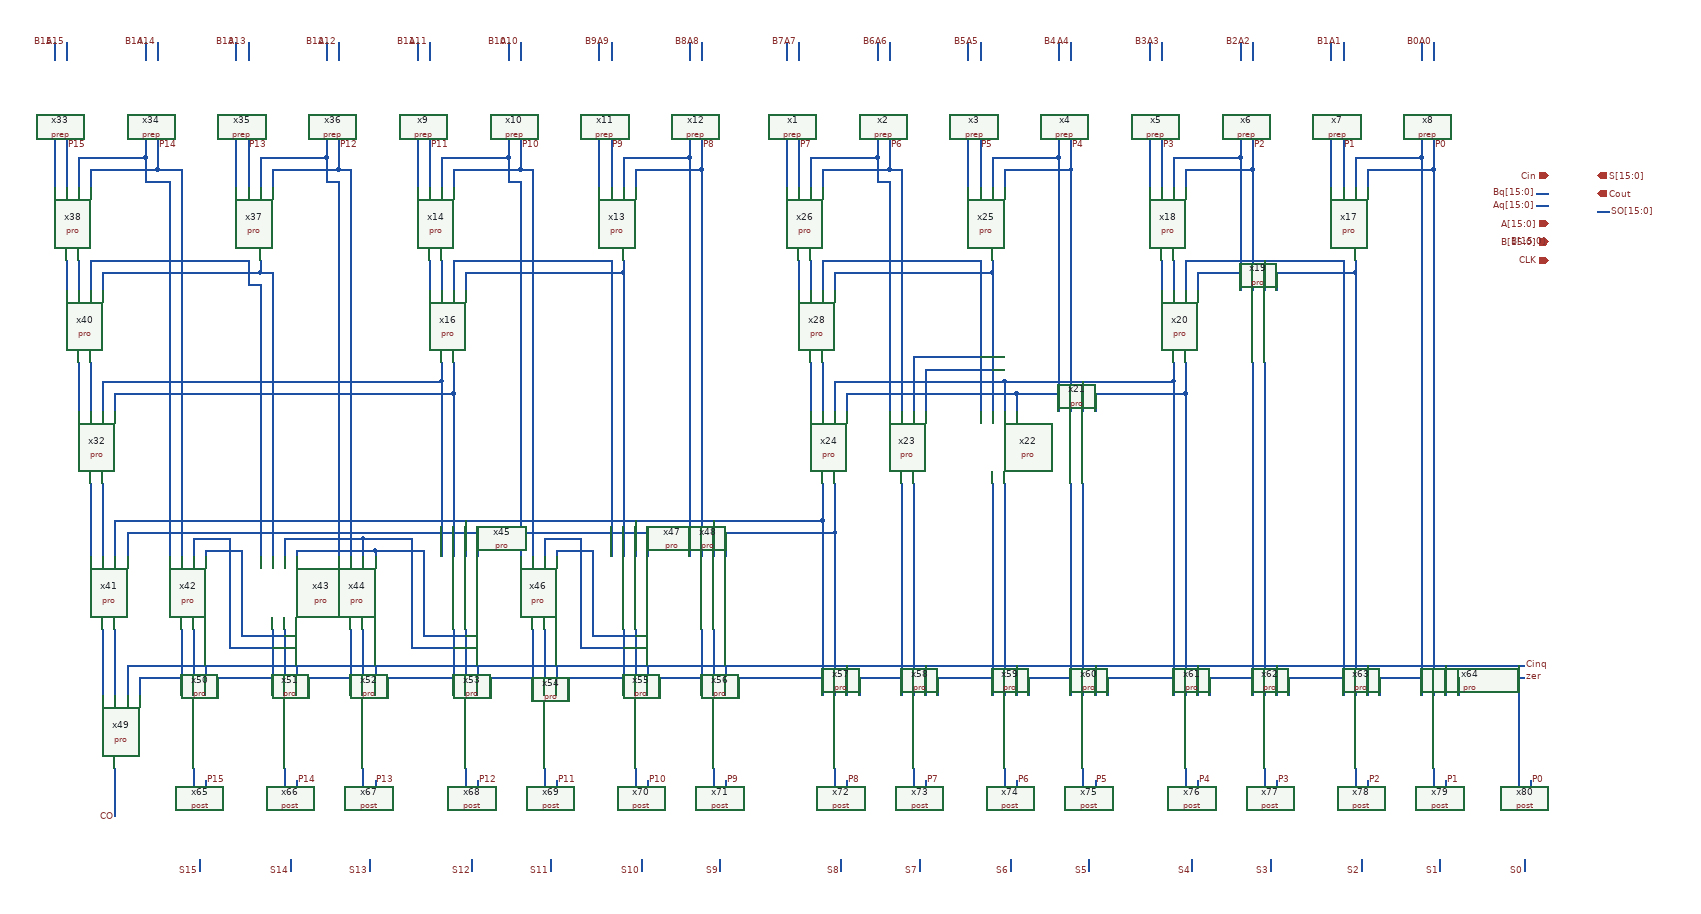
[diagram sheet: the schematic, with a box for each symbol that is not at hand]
v {xschem version=3.4.6 file_version=1.2}
G {}
K {}
V {}
S {}
E {}
N 950 -340 950 -290 {lab=P0}
N 840 -290 840 -260 {lab=P0}
N 930 -340 930 -310 {lab=#net1}
N 820 -310 820 -260 {lab=#net1}
N 800 -340 800 -260 {lab=P1}
N 780 -340 780 -260 {lab=#net2}
N 820 -310 930 -310 {lab=#net1}
N 840 -290 950 -290 {lab=P0}
N 480 -340 480 -260 {lab=#net3}
N 500 -340 500 -260 {lab=P3}
N 520 -310 520 -260 {lab=#net4}
N 520 -310 630 -310 {lab=#net4}
N 630 -340 630 -310 {lab=#net4}
N 650 -340 650 -290 {lab=P2}
N 540 -290 650 -290 {lab=P2}
N 540 -290 540 -260 {lab=P2}
N 500 -140 500 -90 {lab=#net5}
N 520 -140 520 -90 {lab=#net6}
N 540 -140 540 -90 {lab=#net7}
N 540 -140 800 -140 {lab=#net7}
N 560 -120 560 -90 {lab=#net8}
N 560 -120 820 -120 {lab=#net8}
N 820 -140 820 -120 {lab=#net8}
N 630 -310 630 -100 {lab=#net4}
N 650 -290 650 -100 {lab=P2}
N 670 -140 670 -100 {lab=#net7}
N 350 -340 350 -290 {lab=P4}
N 240 -290 240 -260 {lab=P4}
N 330 -340 330 -310 {lab=#net9}
N 220 -310 220 -260 {lab=#net9}
N 200 -340 200 -260 {lab=P5}
N 180 -340 180 -260 {lab=#net10}
N 220 -310 330 -310 {lab=#net9}
N 240 -290 350 -290 {lab=P4}
N -120 -340 -120 -260 {lab=#net11}
N -100 -340 -100 -260 {lab=P7}
N -80 -310 -80 -260 {lab=#net12}
N -80 -310 30 -310 {lab=#net12}
N 30 -340 30 -310 {lab=#net12}
N 50 -340 50 -290 {lab=P6}
N -60 -290 50 -290 {lab=P6}
N -60 -290 -60 -260 {lab=P6}
N -100 -140 -100 -90 {lab=#net13}
N -80 -140 -80 -90 {lab=#net14}
N -60 -140 -60 -90 {lab=#net15}
N -60 -140 200 -140 {lab=#net15}
N -40 -120 -40 -90 {lab=#net16}
N -40 -120 220 -120 {lab=#net16}
N 220 -140 220 -120 {lab=#net16}
N 630 -100 630 -90 {lab=#net4}
N 650 -100 650 -90 {lab=P2}
N 670 -100 670 -90 {lab=#net7}
N 520 30 520 60 {lab=#net17}
N -40 60 -40 110 {lab=#net17}
N 540 30 540 80 {lab=#net18}
N -20 80 -20 110 {lab=#net18}
N -80 30 -80 110 {lab=#net19}
N -60 30 -60 110 {lab=#net20}
N 50 30 50 110 {lab=#net12}
N 70 30 70 110 {lab=P6}
N 200 -140 200 110 {lab=#net15}
N 220 -120 220 110 {lab=#net16}
N 240 60 240 110 {lab=#net17}
N 260 80 260 110 {lab=#net18}
N 330 -310 330 110 {lab=#net9}
N 350 -290 350 110 {lab=P4}
N 370 60 370 110 {lab=#net17}
N 390 80 390 110 {lab=#net18}
N -260 -340 -260 -290 {lab=P8}
N -370 -290 -370 -260 {lab=P8}
N -280 -340 -280 -310 {lab=#net21}
N -390 -310 -390 -260 {lab=#net21}
N -410 -340 -410 -260 {lab=P9}
N -430 -340 -430 -260 {lab=#net22}
N -390 -310 -280 -310 {lab=#net21}
N -370 -290 -260 -290 {lab=P8}
N -730 -340 -730 -260 {lab=#net23}
N -710 -340 -710 -260 {lab=P11}
N -690 -310 -690 -260 {lab=#net24}
N -690 -310 -580 -310 {lab=#net24}
N -580 -340 -580 -310 {lab=#net24}
N -560 -340 -560 -290 {lab=P10}
N -670 -290 -560 -290 {lab=P10}
N -670 -290 -670 -260 {lab=P10}
N -710 -140 -710 -90 {lab=#net25}
N -690 -140 -690 -90 {lab=#net26}
N -670 -140 -670 -90 {lab=#net27}
N -670 -140 -410 -140 {lab=#net27}
N -650 -120 -650 -90 {lab=#net28}
N -650 -120 -390 -120 {lab=#net28}
N -390 -140 -390 -120 {lab=#net28}
N -860 -340 -860 -290 {lab=P12}
N -970 -290 -970 -260 {lab=P12}
N -880 -340 -880 -310 {lab=#net29}
N -990 -310 -990 -260 {lab=#net29}
N -1010 -340 -1010 -260 {lab=P13}
N -1030 -340 -1030 -260 {lab=#net30}
N -990 -310 -880 -310 {lab=#net29}
N -970 -290 -860 -290 {lab=P12}
N -1330 -340 -1330 -260 {lab=#net31}
N -1310 -340 -1310 -260 {lab=P15}
N -1290 -310 -1290 -260 {lab=#net32}
N -1290 -310 -1180 -310 {lab=#net32}
N -1180 -340 -1180 -310 {lab=#net32}
N -1160 -340 -1160 -290 {lab=P14}
N -1270 -290 -1160 -290 {lab=P14}
N -1270 -290 -1270 -260 {lab=P14}
N -1310 -140 -1310 -90 {lab=#net33}
N -1290 -140 -1290 -90 {lab=#net34}
N -1270 -140 -1270 -90 {lab=#net35}
N -1270 -140 -1010 -140 {lab=#net35}
N -1250 -120 -1250 -90 {lab=#net36}
N -1250 -120 -990 -120 {lab=#net36}
N -990 -140 -990 -120 {lab=#net36}
N -690 30 -690 60 {lab=#net37}
N -1250 60 -690 60 {lab=#net37}
N -1250 60 -1250 110 {lab=#net37}
N -670 30 -670 80 {lab=#net38}
N -1230 80 -670 80 {lab=#net38}
N -1230 80 -1230 110 {lab=#net38}
N -1290 30 -1290 110 {lab=#net39}
N -1270 30 -1270 110 {lab=#net40}
N -1270 230 -1270 350 {lab=#net41}
N -1250 230 -1250 350 {lab=#net42}
N -1140 230 -1140 350 {lab=#net32}
N -1120 230 -1120 350 {lab=P14}
N -990 230 -990 350 {lab=#net35}
N -970 230 -970 350 {lab=#net36}
N -860 230 -860 350 {lab=#net29}
N -840 230 -840 350 {lab=P12}
N -690 60 -690 350 {lab=#net37}
N -670 80 -670 350 {lab=#net38}
N -560 30 -560 350 {lab=#net24}
N -540 30 -540 350 {lab=P10}
N -410 -140 -410 350 {lab=#net27}
N -390 -120 -390 350 {lab=#net28}
N -280 -310 -280 350 {lab=#net21}
N -260 -290 -260 350 {lab=P8}
N -60 230 -60 290 {lab=#net43}
N -1230 290 -60 290 {lab=#net43}
N -1230 290 -1230 350 {lab=#net43}
N -1210 310 -1210 350 {lab=#net44}
N -1210 310 -40 310 {lab=#net44}
N -40 230 -40 310 {lab=#net44}
N -220 310 -220 350 {lab=#net44}
N -240 290 -240 350 {lab=#net43}
N -350 310 -350 350 {lab=#net44}
N -370 290 -370 350 {lab=#net43}
N -630 310 -630 350 {lab=#net44}
N -650 290 -650 350 {lab=#net43}
N -1250 470 -1250 580 {lab=#net45}
N -1230 470 -1230 580 {lab=#net46}
N -1120 470 -1120 580 {lab=#net47}
N -1100 470 -1100 580 {lab=#net48}
N -970 470 -970 580 {lab=#net49}
N -950 470 -950 580 {lab=#net50}
N -840 470 -840 580 {lab=#net51}
N -820 470 -820 580 {lab=#net52}
N -670 470 -670 580 {lab=#net53}
N -650 470 -650 580 {lab=#net54}
N -540 470 -540 590 {lab=#net55}
N -520 470 -520 580 {lab=#net56}
N -390 470 -390 580 {lab=#net57}
N -370 470 -370 580 {lab=#net58}
N -260 470 -260 580 {lab=#net59}
N -240 470 -240 580 {lab=#net60}
N -60 290 -60 580 {lab=#net43}
N -40 310 -40 580 {lab=#net44}
N 70 230 70 580 {lab=#net61}
N 90 230 90 580 {lab=#net62}
N 220 230 220 580 {lab=#net63}
N 240 230 240 580 {lab=#net64}
N 350 230 350 580 {lab=#net65}
N 370 230 370 580 {lab=#net66}
N 520 60 520 580 {lab=#net17}
N 540 80 540 580 {lab=#net18}
N 650 30 650 580 {lab=#net67}
N 670 30 670 580 {lab=#net68}
N 800 -140 800 580 {lab=#net7}
N 820 -120 820 580 {lab=#net8}
N 930 -310 930 580 {lab=#net1}
N 950 -290 950 580 {lab=P0}
N -1210 530 -1210 580 {lab=Cinq}
N -1210 530 1100 530 {lab=Cinq}
N -1190 550 -1190 580 {lab=zer}
N -1190 550 1100 550 {lab=zer}
N 990 550 990 580 {lab=zer}
N 970 530 970 580 {lab=Cinq}
N 860 550 860 580 {lab=zer}
N 840 530 840 580 {lab=Cinq}
N 710 550 710 580 {lab=zer}
N 690 530 690 580 {lab=Cinq}
N 560 530 560 580 {lab=Cinq}
N 580 550 580 580 {lab=zer}
N 410 550 410 580 {lab=zer}
N 390 530 390 580 {lab=Cinq}
N 280 550 280 580 {lab=zer}
N 260 530 260 580 {lab=Cinq}
N 130 550 130 580 {lab=zer}
N 110 530 110 580 {lab=Cinq}
N 0 550 0 580 {lab=zer}
N -20 530 -20 580 {lab=Cinq}
N -200 550 -200 580 {lab=zer}
N -220 530 -220 580 {lab=Cinq}
N -330 550 -330 580 {lab=zer}
N -350 530 -350 580 {lab=Cinq}
N -480 550 -480 580 {lab=zer}
N -500 530 -500 580 {lab=Cinq}
N -610 550 -610 580 {lab=zer}
N -630 530 -630 580 {lab=Cinq}
N -780 550 -780 580 {lab=zer}
N -800 530 -800 580 {lab=Cinq}
N -910 550 -910 580 {lab=zer}
N -930 530 -930 580 {lab=Cinq}
N -1060 550 -1060 580 {lab=zer}
N -1080 530 -1080 580 {lab=Cinq}
N -1230 700 -1230 780 {lab=CO}
N -1100 700 -1100 730 {lab=#net69}
N -950 700 -950 730 {lab=#net70}
N -820 700 -820 730 {lab=#net71}
N -650 700 -650 730 {lab=#net72}
N -520 700 -520 730 {lab=#net73}
N -370 700 -370 730 {lab=#net74}
N -240 700 -240 730 {lab=#net75}
N -40 700 -40 730 {lab=#net76}
N 90 700 90 730 {lab=#net77}
N 240 700 240 730 {lab=#net78}
N 370 700 370 730 {lab=#net79}
N 540 700 540 730 {lab=#net80}
N 670 700 670 730 {lab=#net81}
N 820 700 820 730 {lab=#net82}
N 950 700 950 730 {lab=#net83}
N -1330 -500 -1330 -470 {lab=B15}
N -1310 -500 -1310 -470 {lab=A15}
N -1180 -500 -1180 -470 {lab=B14}
N -1160 -500 -1160 -470 {lab=A14}
N -1030 -500 -1030 -470 {lab=B13}
N -1010 -500 -1010 -470 {lab=A13}
N -880 -500 -880 -470 {lab=B12}
N -860 -500 -860 -470 {lab=A12}
N -730 -500 -730 -470 {lab=B11}
N -710 -500 -710 -470 {lab=A11}
N -580 -500 -580 -470 {lab=B10}
N -560 -500 -560 -470 {lab=A10}
N -430 -500 -430 -470 {lab=B9}
N -410 -500 -410 -470 {lab=A9}
N -280 -500 -280 -470 {lab=B8}
N -260 -500 -260 -470 {lab=A8}
N -120 -500 -120 -470 {lab=B7}
N -100 -500 -100 -470 {lab=A7}
N 30 -500 30 -470 {lab=B6}
N 50 -500 50 -470 {lab=A6}
N 180 -500 180 -470 {lab=B5}
N 200 -500 200 -470 {lab=A5}
N 330 -500 330 -470 {lab=B4}
N 350 -500 350 -470 {lab=A4}
N 480 -500 480 -470 {lab=B3}
N 500 -500 500 -470 {lab=A3}
N 630 -500 630 -470 {lab=B2}
N 650 -500 650 -470 {lab=A2}
N 780 -500 780 -470 {lab=B1}
N 800 -500 800 -470 {lab=A1}
N 930 -500 930 -470 {lab=B0}
N 950 -500 950 -470 {lab=A0}
N 1090 530 1090 730 {lab=Cinq}
N 1110 720 1110 730 {lab=P0}
N 970 720 970 730 {lab=P1}
N 840 720 840 730 {lab=P2}
N 690 720 690 730 {lab=P3}
N 560 720 560 730 {lab=P4}
N 390 720 390 730 {lab=P5}
N 260 720 260 730 {lab=P6}
N 110 720 110 730 {lab=P7}
N -20 720 -20 730 {lab=P8}
N -220 720 -220 730 {lab=P9}
N -350 720 -350 730 {lab=P10}
N -500 720 -500 730 {lab=P11}
N -630 720 -630 730 {lab=P12}
N -800 720 -800 730 {lab=P13}
N -930 720 -930 730 {lab=P14}
N -1080 720 -1080 730 {lab=P15}
N 1100 850 1100 870 {lab=S0}
N 960 850 960 870 {lab=S1}
N 830 850 830 870 {lab=S2}
N 680 850 680 870 {lab=S3}
N 550 850 550 870 {lab=S4}
N 380 850 380 870 {lab=S5}
N 250 850 250 870 {lab=S6}
N 100 850 100 870 {lab=S7}
N -30 850 -30 870 {lab=S8}
N -230 850 -230 870 {lab=S9}
N -360 850 -360 870 {lab=S10}
N -510 850 -510 870 {lab=S11}
N -640 850 -640 870 {lab=S12}
N -810 850 -810 870 {lab=S13}
N -940 850 -940 870 {lab=S14}
N -1090 850 -1090 870 {lab=S15}
N 690 -120 690 -90 {lab=#net8}
N 50 -20 50 30 {lab=#net12}
N 70 -40 70 30 {lab=P6}
N 240 60 520 60 {lab=#net17}
N 260 80 540 80 {lab=#net18}
N 90 20 90 110 {lab=#net15}
N 90 20 200 20 {lab=#net15}
N 110 40 110 110 {lab=#net16}
N 110 40 210 40 {lab=#net16}
N 210 40 220 40 {lab=#net16}
N -40 60 240 60 {lab=#net17}
N -20 80 260 80 {lab=#net18}
N 70 -290 70 -40 {lab=P6}
N 50 -290 70 -290 {lab=P6}
N 30 -310 30 -270 {lab=#net12}
N 30 -270 50 -270 {lab=#net12}
N 50 -270 50 -20 {lab=#net12}
N -440 480 -370 480 {lab=#net58}
N -440 340 -440 480 {lab=#net58}
N -500 340 -440 340 {lab=#net58}
N -500 340 -500 350 {lab=#net58}
N -460 500 -390 500 {lab=#net57}
N -460 320 -460 500 {lab=#net57}
N -520 320 -460 320 {lab=#net57}
N -520 320 -520 350 {lab=#net57}
N -580 -310 -580 -270 {lab=#net24}
N -580 -270 -560 -270 {lab=#net24}
N -560 -270 -560 30 {lab=#net24}
N -540 -290 -540 30 {lab=P10}
N -560 -290 -540 -290 {lab=P10}
N -720 480 -650 480 {lab=#net54}
N -720 340 -720 480 {lab=#net54}
N -800 340 -720 340 {lab=#net54}
N -800 340 -800 350 {lab=#net54}
N -740 500 -670 500 {lab=#net53}
N -740 320 -740 500 {lab=#net53}
N -820 320 -740 320 {lab=#net53}
N -820 320 -820 350 {lab=#net53}
N -860 -270 -860 230 {lab=#net29}
N -880 -270 -860 -270 {lab=#net29}
N -880 -310 -880 -270 {lab=#net29}
N -860 -290 -840 -290 {lab=P12}
N -840 -290 -840 230 {lab=P12}
N -950 320 -820 320 {lab=#net53}
N -950 320 -950 350 {lab=#net53}
N -930 340 -930 350 {lab=#net54}
N -930 340 -800 340 {lab=#net54}
N -990 -120 -970 -120 {lab=#net36}
N -970 -120 -970 230 {lab=#net36}
N -1010 -140 -1010 -100 {lab=#net35}
N -1010 -100 -990 -100 {lab=#net35}
N -990 -100 -990 230 {lab=#net35}
N -1020 480 -950 480 {lab=#net50}
N -1020 340 -1020 480 {lab=#net50}
N -1080 340 -1020 340 {lab=#net50}
N -1080 340 -1080 350 {lab=#net50}
N -1040 500 -970 500 {lab=#net49}
N -1040 330 -1040 500 {lab=#net49}
N -1100 330 -1100 350 {lab=#net49}
N -1100 320 -1040 320 {lab=#net49}
N -1040 320 -1040 330 {lab=#net49}
N -1100 320 -1100 330 {lab=#net49}
N -1180 -310 -1180 -270 {lab=#net32}
N -1180 -270 -1160 -270 {lab=#net32}
N -1160 -270 -1150 -270 {lab=#net32}
N -1150 -270 -1140 -270 {lab=#net32}
N -1140 -270 -1140 230 {lab=#net32}
N -1120 -290 -1120 230 {lab=P14}
N -1160 -290 -1120 -290 {lab=P14}
N 1120 -230 1140 -230 {lab=Aq[15:0]}
N 1120 -250 1140 -250 {lab=Bq[15:0]}
N 1220 -220 1240 -220 {lab=SO[15:0]}
C {/home/EE23B038/ee5311/tutorial_9/prep.sym} 480 -390 0 0 {name=x5}
C {/home/EE23B038/ee5311/tutorial_9/prep.sym} 630 -390 0 0 {name=x6}
C {/home/EE23B038/ee5311/tutorial_9/prep.sym} 780 -390 0 0 {name=x7}
C {/home/EE23B038/ee5311/tutorial_9/prep.sym} 930 -390 0 0 {name=x8}
C {/home/EE23B038/ee5311/tutorial_9/pro.sym} 790 -190 0 0 {name=x17}
C {/home/EE23B038/ee5311/tutorial_9/pro.sym} 490 -190 0 0 {name=x18}
C {/home/EE23B038/ee5311/tutorial_9/pro.sym} 640 -20 0 0 {name=x19}
C {/home/EE23B038/ee5311/tutorial_9/pro.sym} 510 -20 0 0 {name=x20}
C {/home/EE23B038/ee5311/tutorial_9/pro.sym} 340 180 0 0 {name=x21}
C {/home/EE23B038/ee5311/tutorial_9/pro.sym} 210 180 0 0 {name=x22}
C {/home/EE23B038/ee5311/tutorial_9/pro.sym} 60 180 0 0 {name=x23}
C {/home/EE23B038/ee5311/tutorial_9/pro.sym} -70 180 0 0 {name=x24}
C {/home/EE23B038/ee5311/tutorial_9/prep.sym} -120 -390 0 0 {name=x1}
C {/home/EE23B038/ee5311/tutorial_9/prep.sym} 30 -390 0 0 {name=x2}
C {/home/EE23B038/ee5311/tutorial_9/prep.sym} 180 -390 0 0 {name=x3}
C {/home/EE23B038/ee5311/tutorial_9/prep.sym} 330 -390 0 0 {name=x4}
C {/home/EE23B038/ee5311/tutorial_9/pro.sym} 190 -190 0 0 {name=x25}
C {/home/EE23B038/ee5311/tutorial_9/pro.sym} -110 -190 0 0 {name=x26}
C {/home/EE23B038/ee5311/tutorial_9/pro.sym} -90 -20 0 0 {name=x28}
C {/home/EE23B038/ee5311/tutorial_9/prep.sym} -730 -390 0 0 {name=x9}
C {/home/EE23B038/ee5311/tutorial_9/prep.sym} -580 -390 0 0 {name=x10}
C {/home/EE23B038/ee5311/tutorial_9/prep.sym} -430 -390 0 0 {name=x11}
C {/home/EE23B038/ee5311/tutorial_9/prep.sym} -280 -390 0 0 {name=x12}
C {/home/EE23B038/ee5311/tutorial_9/pro.sym} -420 -190 0 0 {name=x13}
C {/home/EE23B038/ee5311/tutorial_9/pro.sym} -720 -190 0 0 {name=x14}
C {/home/EE23B038/ee5311/tutorial_9/pro.sym} -700 -20 0 0 {name=x16}
C {/home/EE23B038/ee5311/tutorial_9/pro.sym} -1280 180 0 0 {name=x32}
C {/home/EE23B038/ee5311/tutorial_9/prep.sym} -1330 -390 0 0 {name=x33}
C {/home/EE23B038/ee5311/tutorial_9/prep.sym} -1180 -390 0 0 {name=x34}
C {/home/EE23B038/ee5311/tutorial_9/prep.sym} -1030 -390 0 0 {name=x35}
C {/home/EE23B038/ee5311/tutorial_9/prep.sym} -880 -390 0 0 {name=x36}
C {/home/EE23B038/ee5311/tutorial_9/pro.sym} -1020 -190 0 0 {name=x37}
C {/home/EE23B038/ee5311/tutorial_9/pro.sym} -1320 -190 0 0 {name=x38}
C {/home/EE23B038/ee5311/tutorial_9/pro.sym} -1300 -20 0 0 {name=x40}
C {/home/EE23B038/ee5311/tutorial_9/pro.sym} -1260 420 0 0 {name=x41}
C {/home/EE23B038/ee5311/tutorial_9/pro.sym} -1130 420 0 0 {name=x42}
C {/home/EE23B038/ee5311/tutorial_9/pro.sym} -980 420 0 0 {name=x43}
C {/home/EE23B038/ee5311/tutorial_9/pro.sym} -850 420 0 0 {name=x44}
C {/home/EE23B038/ee5311/tutorial_9/pro.sym} -680 420 0 0 {name=x45}
C {/home/EE23B038/ee5311/tutorial_9/pro.sym} -550 420 0 0 {name=x46}
C {/home/EE23B038/ee5311/tutorial_9/pro.sym} -400 420 0 0 {name=x47}
C {/home/EE23B038/ee5311/tutorial_9/pro.sym} -270 420 0 0 {name=x48}
C {/home/EE23B038/ee5311/tutorial_9/pro.sym} -1240 650 0 0 {name=x49}
C {/home/EE23B038/ee5311/tutorial_9/pro.sym} -1110 650 0 0 {name=x50}
C {/home/EE23B038/ee5311/tutorial_9/pro.sym} -960 650 0 0 {name=x51}
C {/home/EE23B038/ee5311/tutorial_9/pro.sym} -830 650 0 0 {name=x52}
C {/home/EE23B038/ee5311/tutorial_9/pro.sym} -660 650 0 0 {name=x53}
C {/home/EE23B038/ee5311/tutorial_9/pro.sym} -530 650 0 0 {name=x54}
C {/home/EE23B038/ee5311/tutorial_9/pro.sym} -380 650 0 0 {name=x55}
C {/home/EE23B038/ee5311/tutorial_9/pro.sym} -250 650 0 0 {name=x56}
C {/home/EE23B038/ee5311/tutorial_9/pro.sym} -50 650 0 0 {name=x57}
C {/home/EE23B038/ee5311/tutorial_9/pro.sym} 80 650 0 0 {name=x58}
C {/home/EE23B038/ee5311/tutorial_9/pro.sym} 230 650 0 0 {name=x59}
C {/home/EE23B038/ee5311/tutorial_9/pro.sym} 360 650 0 0 {name=x60}
C {/home/EE23B038/ee5311/tutorial_9/pro.sym} 530 650 0 0 {name=x61}
C {/home/EE23B038/ee5311/tutorial_9/pro.sym} 660 650 0 0 {name=x62}
C {/home/EE23B038/ee5311/tutorial_9/pro.sym} 810 650 0 0 {name=x63}
C {/home/EE23B038/ee5311/tutorial_9/pro.sym} 940 650 0 0 {name=x64}
C {lab_pin.sym} 1100 550 2 0 {name=p2 verilog_type=logic lab=zer}
C {noconn.sym} -1230 780 0 0 {name=l1}
C {noconn.sym} 1100 530 1 0 {name=l2}
C {/home/EE23B038/ee5311/tutorial_9/post.sym} -1090 800 0 0 {name=x65}
C {/home/EE23B038/ee5311/tutorial_9/post.sym} -940 800 0 0 {name=x66}
C {/home/EE23B038/ee5311/tutorial_9/post.sym} -810 800 0 0 {name=x67}
C {/home/EE23B038/ee5311/tutorial_9/post.sym} -640 800 0 0 {name=x68}
C {/home/EE23B038/ee5311/tutorial_9/post.sym} -510 800 0 0 {name=x69}
C {/home/EE23B038/ee5311/tutorial_9/post.sym} -360 800 0 0 {name=x70}
C {/home/EE23B038/ee5311/tutorial_9/post.sym} -230 800 0 0 {name=x71}
C {/home/EE23B038/ee5311/tutorial_9/post.sym} -30 800 0 0 {name=x72}
C {/home/EE23B038/ee5311/tutorial_9/post.sym} 100 800 0 0 {name=x73}
C {/home/EE23B038/ee5311/tutorial_9/post.sym} 250 800 0 0 {name=x74}
C {/home/EE23B038/ee5311/tutorial_9/post.sym} 380 800 0 0 {name=x75}
C {/home/EE23B038/ee5311/tutorial_9/post.sym} 550 800 0 0 {name=x76}
C {/home/EE23B038/ee5311/tutorial_9/post.sym} 680 800 0 0 {name=x77}
C {/home/EE23B038/ee5311/tutorial_9/post.sym} 830 800 0 0 {name=x78}
C {/home/EE23B038/ee5311/tutorial_9/post.sym} 960 800 0 0 {name=x79}
C {lab_pin.sym} -1330 -500 1 0 {name=p7 verilog_type=logic lab=B15}
C {lab_pin.sym} -1310 -500 1 0 {name=p8 verilog_type=logic lab=A15}
C {lab_pin.sym} -1180 -500 1 0 {name=p9 verilog_type=logic lab=B14}
C {lab_pin.sym} -1160 -500 1 0 {name=p10 verilog_type=logic lab=A14}
C {lab_pin.sym} -1030 -500 1 0 {name=p11 verilog_type=logic lab=B13}
C {lab_pin.sym} -1010 -500 1 0 {name=p12 verilog_type=logic lab=A13}
C {lab_pin.sym} -880 -500 1 0 {name=p13 verilog_type=logic lab=B12}
C {lab_pin.sym} -860 -500 1 0 {name=p14 verilog_type=logic lab=A12}
C {lab_pin.sym} -730 -500 1 0 {name=p15 verilog_type=logic lab=B11}
C {lab_pin.sym} -710 -500 1 0 {name=p16 verilog_type=logic lab=A11}
C {lab_pin.sym} -580 -500 1 0 {name=p17 verilog_type=logic lab=B10}
C {lab_pin.sym} -560 -500 1 0 {name=p18 verilog_type=logic lab=A10}
C {lab_pin.sym} -430 -500 1 0 {name=p19 verilog_type=logic lab=B9}
C {lab_pin.sym} -410 -500 1 0 {name=p20 verilog_type=logic lab=A9}
C {lab_pin.sym} -280 -500 1 0 {name=p21 verilog_type=logic lab=B8}
C {lab_pin.sym} -260 -500 1 0 {name=p22 verilog_type=logic lab=A8}
C {lab_pin.sym} -120 -500 1 0 {name=p23 verilog_type=logic lab=B7}
C {lab_pin.sym} -100 -500 1 0 {name=p24 verilog_type=logic lab=A7}
C {lab_pin.sym} 30 -500 1 0 {name=p25 verilog_type=logic lab=B6}
C {lab_pin.sym} 50 -500 1 0 {name=p26 verilog_type=logic lab=A6}
C {lab_pin.sym} 180 -500 1 0 {name=p27 verilog_type=logic lab=B5}
C {lab_pin.sym} 200 -500 1 0 {name=p28 verilog_type=logic lab=A5}
C {lab_pin.sym} 330 -500 1 0 {name=p29 verilog_type=logic lab=B4}
C {lab_pin.sym} 350 -500 1 0 {name=p30 verilog_type=logic lab=A4}
C {lab_pin.sym} 480 -500 1 0 {name=p31 verilog_type=logic lab=B3}
C {lab_pin.sym} 500 -500 1 0 {name=p32 verilog_type=logic lab=A3}
C {lab_pin.sym} 630 -500 1 0 {name=p33 verilog_type=logic lab=B2}
C {lab_pin.sym} 650 -500 1 0 {name=p34 verilog_type=logic lab=A2}
C {lab_pin.sym} 780 -500 1 0 {name=p35 verilog_type=logic lab=B1}
C {lab_pin.sym} 800 -500 1 0 {name=p36 verilog_type=logic lab=A1}
C {lab_pin.sym} 930 -500 1 0 {name=p37 verilog_type=logic lab=B0}
C {lab_pin.sym} 950 -500 1 0 {name=p38 verilog_type=logic lab=A0}
C {lab_pin.sym} 950 -330 2 0 {name=p39 verilog_type=logic lab=P0}
C {lab_pin.sym} 800 -330 2 0 {name=p40 verilog_type=logic lab=P1}
C {lab_pin.sym} 650 -330 2 0 {name=p41 verilog_type=logic lab=P2}
C {lab_pin.sym} 500 -330 2 0 {name=p42 verilog_type=logic lab=P3}
C {lab_pin.sym} 350 -330 2 0 {name=p43 verilog_type=logic lab=P4}
C {lab_pin.sym} 200 -330 2 0 {name=p44 verilog_type=logic lab=P5}
C {lab_pin.sym} 50 -330 2 0 {name=p45 verilog_type=logic lab=P6}
C {lab_pin.sym} -100 -330 2 0 {name=p46 verilog_type=logic lab=P7}
C {lab_pin.sym} -260 -330 2 0 {name=p47 verilog_type=logic lab=P8}
C {lab_pin.sym} -410 -330 2 0 {name=p48 verilog_type=logic lab=P9}
C {lab_pin.sym} -560 -330 2 0 {name=p49 verilog_type=logic lab=P10}
C {lab_pin.sym} -710 -330 2 0 {name=p50 verilog_type=logic lab=P11}
C {lab_pin.sym} -860 -330 2 0 {name=p51 verilog_type=logic lab=P12}
C {lab_pin.sym} -1010 -330 2 0 {name=p52 verilog_type=logic lab=P13}
C {lab_pin.sym} -1160 -330 2 0 {name=p53 verilog_type=logic lab=P14}
C {lab_pin.sym} -1310 -330 2 0 {name=p54 verilog_type=logic lab=P15}
C {lab_pin.sym} -630 720 2 0 {name=p55 verilog_type=logic lab=P12}
C {lab_pin.sym} -800 720 2 0 {name=p56 verilog_type=logic lab=P13}
C {lab_pin.sym} -930 720 2 0 {name=p57 verilog_type=logic lab=P14}
C {lab_pin.sym} -1080 720 2 0 {name=p58 verilog_type=logic lab=P15}
C {lab_pin.sym} -20 720 2 0 {name=p59 verilog_type=logic lab=P8}
C {lab_pin.sym} -220 720 2 0 {name=p60 verilog_type=logic lab=P9}
C {lab_pin.sym} -350 720 2 0 {name=p61 verilog_type=logic lab=P10}
C {lab_pin.sym} -500 720 2 0 {name=p62 verilog_type=logic lab=P11}
C {lab_pin.sym} 840 720 2 0 {name=p63 verilog_type=logic lab=P2}
C {lab_pin.sym} 690 720 2 0 {name=p64 verilog_type=logic lab=P3}
C {lab_pin.sym} 560 720 2 0 {name=p65 verilog_type=logic lab=P4}
C {lab_pin.sym} 390 720 2 0 {name=p66 verilog_type=logic lab=P5}
C {lab_pin.sym} 260 720 2 0 {name=p67 verilog_type=logic lab=P6}
C {lab_pin.sym} 110 720 2 0 {name=p68 verilog_type=logic lab=P7}
C {lab_pin.sym} 1110 720 2 0 {name=p69 verilog_type=logic lab=P0}
C {lab_pin.sym} 970 720 2 0 {name=p70 verilog_type=logic lab=P1}
C {/home/EE23B038/ee5311/tutorial_9/post.sym} 1100 800 0 0 {name=x80}
C {lab_pin.sym} 1100 870 0 0 {name=p71 verilog_type=logic lab=S0}
C {lab_pin.sym} 960 870 0 0 {name=p72 verilog_type=logic lab=S1}
C {lab_pin.sym} 830 870 0 0 {name=p73 verilog_type=logic lab=S2}
C {lab_pin.sym} 680 870 0 0 {name=p74 verilog_type=logic lab=S3}
C {lab_pin.sym} 550 870 0 0 {name=p75 verilog_type=logic lab=S4}
C {lab_pin.sym} 380 870 0 0 {name=p76 verilog_type=logic lab=S5}
C {lab_pin.sym} 250 870 0 0 {name=p77 verilog_type=logic lab=S6}
C {lab_pin.sym} 100 870 0 0 {name=p78 verilog_type=logic lab=S7}
C {lab_pin.sym} -30 870 0 0 {name=p79 verilog_type=logic lab=S8}
C {lab_pin.sym} -230 870 0 0 {name=p80 verilog_type=logic lab=S9}
C {lab_pin.sym} -360 870 0 0 {name=p81 verilog_type=logic lab=S10}
C {lab_pin.sym} -510 870 0 0 {name=p82 verilog_type=logic lab=S11}
C {lab_pin.sym} -640 870 0 0 {name=p83 verilog_type=logic lab=S12}
C {lab_pin.sym} -810 870 0 0 {name=p84 verilog_type=logic lab=S13}
C {lab_pin.sym} -940 870 0 0 {name=p85 verilog_type=logic lab=S14}
C {lab_pin.sym} -1090 870 0 0 {name=p86 verilog_type=logic lab=S15}
C {noconn.sym} -1330 -470 0 0 {name=l6}
C {noconn.sym} -1310 -470 0 0 {name=l7}
C {noconn.sym} -1180 -470 0 0 {name=l8}
C {noconn.sym} -1160 -470 0 0 {name=l9}
C {noconn.sym} -1030 -470 0 0 {name=l10}
C {noconn.sym} -1010 -470 0 0 {name=l11}
C {noconn.sym} -880 -470 0 0 {name=l12}
C {noconn.sym} -860 -470 0 0 {name=l13}
C {noconn.sym} -730 -470 0 0 {name=l14}
C {noconn.sym} -710 -470 0 0 {name=l15}
C {noconn.sym} -580 -470 0 0 {name=l16}
C {noconn.sym} -560 -470 0 0 {name=l17}
C {noconn.sym} -430 -470 0 0 {name=l18}
C {noconn.sym} -410 -470 0 0 {name=l19}
C {noconn.sym} -280 -470 0 0 {name=l20}
C {noconn.sym} -260 -470 0 0 {name=l21}
C {noconn.sym} -120 -470 0 0 {name=l22}
C {noconn.sym} -100 -470 0 0 {name=l23}
C {noconn.sym} 30 -470 0 0 {name=l24}
C {noconn.sym} 50 -470 0 0 {name=l25}
C {noconn.sym} 180 -470 0 0 {name=l26}
C {noconn.sym} 200 -470 0 0 {name=l27}
C {noconn.sym} 330 -470 0 0 {name=l28}
C {noconn.sym} 350 -470 0 0 {name=l29}
C {noconn.sym} 480 -470 0 0 {name=l30}
C {noconn.sym} 500 -470 0 0 {name=l31}
C {noconn.sym} 630 -470 0 0 {name=l32}
C {noconn.sym} 650 -470 0 0 {name=l33}
C {noconn.sym} 780 -470 0 0 {name=l34}
C {noconn.sym} 800 -470 0 0 {name=l35}
C {noconn.sym} 930 -470 0 0 {name=l36}
C {noconn.sym} 950 -470 0 0 {name=l37}
C {noconn.sym} -1090 850 0 0 {name=l38}
C {noconn.sym} -940 850 0 0 {name=l39}
C {noconn.sym} -810 850 0 0 {name=l40}
C {noconn.sym} -640 850 0 0 {name=l41}
C {noconn.sym} -510 850 0 0 {name=l42}
C {noconn.sym} -360 850 0 0 {name=l43}
C {noconn.sym} -230 850 0 0 {name=l44}
C {noconn.sym} -30 850 0 0 {name=l45}
C {noconn.sym} 100 850 0 0 {name=l46}
C {noconn.sym} 250 850 0 0 {name=l47}
C {noconn.sym} 380 850 0 0 {name=l48}
C {noconn.sym} 550 850 0 0 {name=l49}
C {noconn.sym} 680 850 0 0 {name=l50}
C {noconn.sym} 830 850 0 0 {name=l51}
C {noconn.sym} 960 850 0 0 {name=l52}
C {noconn.sym} 1100 850 0 0 {name=l53}
C {noconn.sym} 1100 550 3 0 {name=l54}
C {ipin.sym} 1140 -280 0 0 {name=p4 lab=Cin verilog_type=logic}
C {noconn.sym} 1140 -280 1 0 {name=l3}
C {ipin.sym} 1140 -200 0 0 {name=p5 lab=A[15:0] verilog_type=logic}
C {noconn.sym} 1140 -200 1 0 {name=l4}
C {ipin.sym} 1140 -170 0 0 {name=p6 lab=B[15:0] verilog_type=logic}
C {noconn.sym} 1140 -170 1 0 {name=l5
lab=B[15:0]}
C {opin.sym} 1220 -280 0 0 {name=p87 lab=S[15:0] verilog_type=logic}
C {noconn.sym} 1220 -280 1 0 {name=l55}
C {verilog_code.sym} 1040 -60 0 0 {name=s1 string="assign \{A15,A14,A13,A12,A11,A10,A9,A8,A7,A6,A5,A4,A3,A2,A1,A0\} = Aq[15:0];
assign \{B15,B14,B13,B12,B11,B10,B9,B8,B7,B6,B5,B4,B3,B2,B1,B0\} = Bq[15:0];
assign SO[15:0] = \{S15,S14,S13,S12,S11,S10,S9,S8,S7,S6,S5,S4,S3,S2,S1,S0\};
assign zer = 0;
always @(posedge CLK) begin
Aq <= A;
Bq <= B;
Cinq <= Cin;
S <= SO;
Cout <= CO;
end"}
C {lab_pin.sym} 1120 -230 0 0 {name=p88 verilog_type=logic lab=Aq[15:0]}
C {lab_pin.sym} 1120 -250 0 0 {name=p89 verilog_type=logic lab=Bq[15:0]}
C {noconn.sym} 1140 -230 1 0 {name=l56}
C {noconn.sym} 1140 -250 1 0 {name=l57}
C {opin.sym} 1220 -250 0 0 {name=p90 lab=Cout verilog_type=logic}
C {noconn.sym} 1220 -250 1 0 {name=l58}
C {lab_pin.sym} 1240 -220 2 0 {name=p91 verilog_type=logic lab=SO[15:0]}
C {noconn.sym} 1220 -220 1 0 {name=l59}
C {lab_pin.sym} 1100 530 2 0 {name=p1 verilog_type=logic lab=Cinq}
C {lab_pin.sym} -1230 780 3 0 {name=p3 verilog_type=logic lab=CO}
C {ipin.sym} 1140 -140 0 0 {name=p92 lab=CLK verilog_type=logic}
C {noconn.sym} 1140 -140 1 0 {name=l60}
